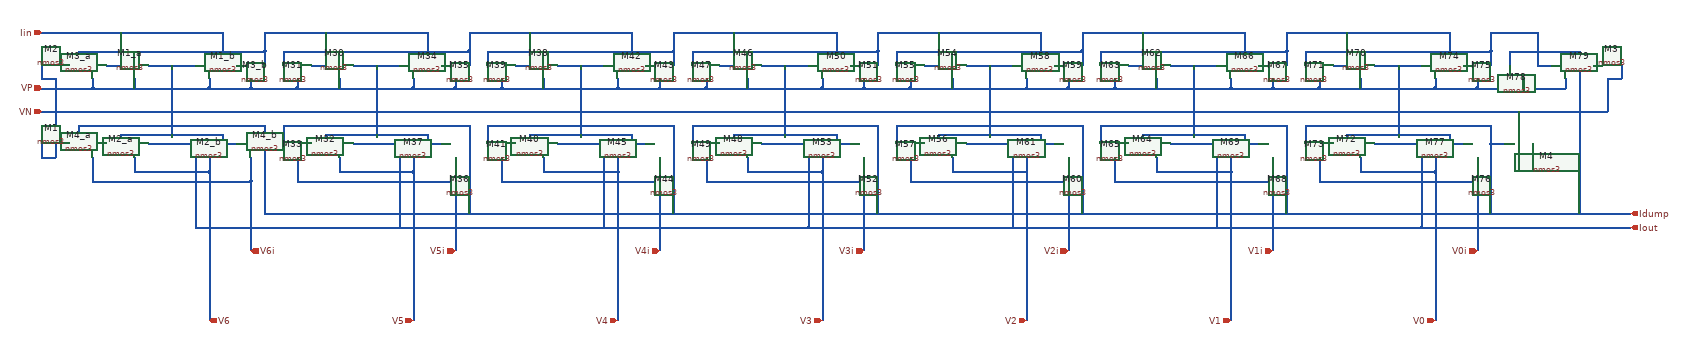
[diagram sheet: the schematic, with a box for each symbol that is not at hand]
v {xschem version=3.4.3 file_version=1.2
}
G {}
K {}
V {}
S {}
E {}
N 210 -770 210 -750 {
lab=VP}
N 210 -750 460 -750 {
lab=VP}
N 460 -770 460 -750 {
lab=VP}
N 300 -770 300 -750 {
lab=VP}
N 460 -750 550 -750 {
lab=VP}
N 550 -770 550 -750 {
lab=VP}
N 100 -750 210 -750 {
lab=VP}
N 330 -800 430 -800 {
lab=#net1}
N 330 -630 430 -630 {
lab=Iout}
N 210 -600 210 -570 {
lab=V6i}
N 300 -600 300 -570 {
lab=V6}
N 460 -600 460 -570 {
lab=V6}
N 240 -630 270 -630 {
lab=#net1}
N 240 -800 270 -800 {
lab=Iin}
N 490 -800 520 -800 {
lab=Iin}
N 180 -830 180 -800 {
lab=#net2}
N 180 -830 580 -830 {
lab=#net2}
N 580 -830 580 -800 {
lab=#net2}
N 580 -870 580 -830 {
lab=#net2}
N 300 -570 460 -570 {
lab=V6}
N 210 -570 210 -550 {
lab=V6i}
N 100 -870 490 -870 {
lab=Iin}
N 490 -870 490 -800 {
lab=Iin}
N 270 -870 270 -800 {
lab=Iin}
N 380 -800 380 -720 {
lab=#net1}
N 270 -650 270 -630 {
lab=#net1}
N 270 -650 490 -650 {
lab=#net1}
N 490 -650 490 -630 {
lab=#net1}
N 380 -720 380 -650 {
lab=#net1}
N 180 -670 180 -630 {
lab=Idump}
N 430 -630 430 -450 {
lab=Iout}
N 430 -450 490 -450 {
lab=Iout}
N 490 -450 620 -450 {
lab=Iout}
N 590 -480 620 -480 {
lab=Idump}
N 580 -870 620 -870 {
lab=#net2}
N 550 -600 550 -550 {
lab=V6i}
N 210 -550 550 -550 {
lab=V6i}
N 490 -630 520 -630 {
lab=#net1}
N 650 -770 650 -750 {
lab=VP}
N 650 -750 900 -750 {
lab=VP}
N 900 -770 900 -750 {
lab=VP}
N 740 -770 740 -750 {
lab=VP}
N 900 -750 990 -750 {
lab=VP}
N 990 -770 990 -750 {
lab=VP}
N 770 -800 870 -800 {
lab=#net3}
N 770 -630 870 -630 {
lab=Iout}
N 650 -600 650 -570 {
lab=V5i}
N 740 -600 740 -570 {
lab=V5}
N 900 -600 900 -570 {
lab=V5}
N 680 -630 710 -630 {
lab=#net3}
N 680 -800 710 -800 {
lab=#net2}
N 930 -800 960 -800 {
lab=#net2}
N 620 -830 620 -800 {
lab=#net4}
N 620 -830 1020 -830 {
lab=#net4}
N 1020 -830 1020 -800 {
lab=#net4}
N 1020 -870 1020 -830 {
lab=#net4}
N 740 -570 900 -570 {
lab=V5}
N 650 -570 650 -550 {
lab=V5i}
N 930 -870 930 -800 {
lab=#net2}
N 710 -870 710 -800 {
lab=#net2}
N 820 -800 820 -720 {
lab=#net3}
N 710 -650 710 -630 {
lab=#net3}
N 710 -650 930 -650 {
lab=#net3}
N 930 -650 930 -630 {
lab=#net3}
N 820 -720 820 -650 {
lab=#net3}
N 620 -670 620 -630 {
lab=Idump}
N 870 -630 870 -450 {
lab=Iout}
N 870 -450 930 -450 {
lab=Iout}
N 930 -450 1060 -450 {
lab=Iout}
N 1030 -480 1060 -480 {
lab=Idump}
N 1020 -870 1060 -870 {
lab=#net4}
N 990 -600 990 -550 {
lab=V5i}
N 650 -550 990 -550 {
lab=V5i}
N 930 -630 960 -630 {
lab=#net3}
N 620 -480 1030 -480 {
lab=Idump}
N 620 -450 870 -450 {
lab=Iout}
N 180 -670 580 -670 {
lab=Idump}
N 580 -670 580 -630 {
lab=Idump}
N 580 -630 580 -480 {
lab=Idump}
N 580 -480 590 -480 {
lab=Idump}
N 620 -670 1020 -670 {
lab=Idump}
N 1020 -670 1020 -630 {
lab=Idump}
N 1020 -630 1020 -480 {
lab=Idump}
N 620 -870 930 -870 {
lab=#net2}
N 1090 -770 1090 -750 {
lab=VP}
N 1090 -750 1340 -750 {
lab=VP}
N 1340 -770 1340 -750 {
lab=VP}
N 1180 -770 1180 -750 {
lab=VP}
N 1340 -750 1430 -750 {
lab=VP}
N 1430 -770 1430 -750 {
lab=VP}
N 1210 -800 1310 -800 {
lab=#net5}
N 1210 -630 1310 -630 {
lab=Iout}
N 1090 -600 1090 -570 {
lab=V4i}
N 1180 -600 1180 -570 {
lab=V4}
N 1340 -600 1340 -570 {
lab=V4}
N 1120 -630 1150 -630 {
lab=#net5}
N 1120 -800 1150 -800 {
lab=#net4}
N 1370 -800 1400 -800 {
lab=#net4}
N 1060 -830 1060 -800 {
lab=#net6}
N 1060 -830 1460 -830 {
lab=#net6}
N 1460 -830 1460 -800 {
lab=#net6}
N 1460 -870 1460 -830 {
lab=#net6}
N 1180 -570 1340 -570 {
lab=V4}
N 1090 -570 1090 -550 {
lab=V4i}
N 1370 -870 1370 -800 {
lab=#net4}
N 1150 -870 1150 -800 {
lab=#net4}
N 1260 -800 1260 -720 {
lab=#net5}
N 1150 -650 1150 -630 {
lab=#net5}
N 1150 -650 1370 -650 {
lab=#net5}
N 1370 -650 1370 -630 {
lab=#net5}
N 1260 -720 1260 -650 {
lab=#net5}
N 1060 -670 1060 -630 {
lab=Idump}
N 1310 -630 1310 -450 {
lab=Iout}
N 1310 -450 1370 -450 {
lab=Iout}
N 1370 -450 1500 -450 {
lab=Iout}
N 1470 -480 1500 -480 {
lab=Idump}
N 1460 -870 1500 -870 {
lab=#net6}
N 1430 -600 1430 -550 {
lab=V4i}
N 1090 -550 1430 -550 {
lab=V4i}
N 1370 -630 1400 -630 {
lab=#net5}
N 1060 -480 1470 -480 {
lab=Idump}
N 1060 -450 1310 -450 {
lab=Iout}
N 1060 -670 1460 -670 {
lab=Idump}
N 1460 -670 1460 -630 {
lab=Idump}
N 1460 -630 1460 -480 {
lab=Idump}
N 1060 -870 1370 -870 {
lab=#net4}
N 1530 -770 1530 -750 {
lab=VP}
N 1530 -750 1780 -750 {
lab=VP}
N 1780 -770 1780 -750 {
lab=VP}
N 1620 -770 1620 -750 {
lab=VP}
N 1780 -750 1870 -750 {
lab=VP}
N 1870 -770 1870 -750 {
lab=VP}
N 1650 -800 1750 -800 {
lab=#net7}
N 1650 -630 1750 -630 {
lab=Iout}
N 1530 -600 1530 -570 {
lab=V3i}
N 1620 -600 1620 -570 {
lab=V3}
N 1780 -600 1780 -570 {
lab=V3}
N 1560 -630 1590 -630 {
lab=#net7}
N 1560 -800 1590 -800 {
lab=#net6}
N 1810 -800 1840 -800 {
lab=#net6}
N 1500 -830 1500 -800 {
lab=#net8}
N 1500 -830 1900 -830 {
lab=#net8}
N 1900 -830 1900 -800 {
lab=#net8}
N 1900 -870 1900 -830 {
lab=#net8}
N 1620 -570 1780 -570 {
lab=V3}
N 1530 -570 1530 -550 {
lab=V3i}
N 1810 -870 1810 -800 {
lab=#net6}
N 1590 -870 1590 -800 {
lab=#net6}
N 1700 -800 1700 -720 {
lab=#net7}
N 1590 -650 1590 -630 {
lab=#net7}
N 1590 -650 1810 -650 {
lab=#net7}
N 1810 -650 1810 -630 {
lab=#net7}
N 1700 -720 1700 -650 {
lab=#net7}
N 1500 -670 1500 -630 {
lab=Idump}
N 1750 -630 1750 -450 {
lab=Iout}
N 1750 -450 1810 -450 {
lab=Iout}
N 1810 -450 1940 -450 {
lab=Iout}
N 1910 -480 1940 -480 {
lab=Idump}
N 1900 -870 1940 -870 {
lab=#net8}
N 1870 -600 1870 -550 {
lab=V3i}
N 1530 -550 1870 -550 {
lab=V3i}
N 1810 -630 1840 -630 {
lab=#net7}
N 1500 -480 1910 -480 {
lab=Idump}
N 1500 -450 1750 -450 {
lab=Iout}
N 1500 -670 1900 -670 {
lab=Idump}
N 1900 -670 1900 -630 {
lab=Idump}
N 1900 -630 1900 -480 {
lab=Idump}
N 1500 -870 1810 -870 {
lab=#net6}
N 1970 -770 1970 -750 {
lab=VP}
N 1970 -750 2220 -750 {
lab=VP}
N 2220 -770 2220 -750 {
lab=VP}
N 2060 -770 2060 -750 {
lab=VP}
N 2220 -750 2310 -750 {
lab=VP}
N 2310 -770 2310 -750 {
lab=VP}
N 2090 -800 2190 -800 {
lab=#net9}
N 2090 -630 2190 -630 {
lab=Iout}
N 1970 -600 1970 -570 {
lab=V2i}
N 2060 -600 2060 -570 {
lab=V2}
N 2220 -600 2220 -570 {
lab=V2}
N 2000 -630 2030 -630 {
lab=#net9}
N 2000 -800 2030 -800 {
lab=#net8}
N 2250 -800 2280 -800 {
lab=#net8}
N 1940 -830 1940 -800 {
lab=#net10}
N 1940 -830 2340 -830 {
lab=#net10}
N 2340 -830 2340 -800 {
lab=#net10}
N 2340 -870 2340 -830 {
lab=#net10}
N 2060 -570 2220 -570 {
lab=V2}
N 1970 -570 1970 -550 {
lab=V2i}
N 2250 -870 2250 -800 {
lab=#net8}
N 2030 -870 2030 -800 {
lab=#net8}
N 2140 -800 2140 -720 {
lab=#net9}
N 2030 -650 2030 -630 {
lab=#net9}
N 2030 -650 2250 -650 {
lab=#net9}
N 2250 -650 2250 -630 {
lab=#net9}
N 2140 -720 2140 -650 {
lab=#net9}
N 1940 -670 1940 -630 {
lab=Idump}
N 2190 -630 2190 -450 {
lab=Iout}
N 2190 -450 2250 -450 {
lab=Iout}
N 2250 -450 2380 -450 {
lab=Iout}
N 2350 -480 2380 -480 {
lab=Idump}
N 2340 -870 2380 -870 {
lab=#net10}
N 2310 -600 2310 -550 {
lab=V2i}
N 1970 -550 2310 -550 {
lab=V2i}
N 2250 -630 2280 -630 {
lab=#net9}
N 1940 -480 2350 -480 {
lab=Idump}
N 1940 -450 2190 -450 {
lab=Iout}
N 1940 -670 2340 -670 {
lab=Idump}
N 2340 -670 2340 -630 {
lab=Idump}
N 2340 -630 2340 -480 {
lab=Idump}
N 1940 -870 2250 -870 {
lab=#net8}
N 2410 -770 2410 -750 {
lab=VP}
N 2410 -750 2660 -750 {
lab=VP}
N 2660 -770 2660 -750 {
lab=VP}
N 2500 -770 2500 -750 {
lab=VP}
N 2660 -750 2750 -750 {
lab=VP}
N 2750 -770 2750 -750 {
lab=VP}
N 2530 -800 2630 -800 {
lab=#net11}
N 2530 -630 2630 -630 {
lab=Iout}
N 2410 -600 2410 -570 {
lab=V1i}
N 2500 -600 2500 -570 {
lab=V1}
N 2660 -600 2660 -570 {
lab=V1}
N 2440 -630 2470 -630 {
lab=#net11}
N 2440 -800 2470 -800 {
lab=#net10}
N 2690 -800 2720 -800 {
lab=#net10}
N 2380 -830 2380 -800 {
lab=#net12}
N 2380 -830 2780 -830 {
lab=#net12}
N 2780 -830 2780 -800 {
lab=#net12}
N 2780 -870 2780 -830 {
lab=#net12}
N 2500 -570 2660 -570 {
lab=V1}
N 2410 -570 2410 -550 {
lab=V1i}
N 2690 -870 2690 -800 {
lab=#net10}
N 2470 -870 2470 -800 {
lab=#net10}
N 2580 -800 2580 -720 {
lab=#net11}
N 2470 -650 2470 -630 {
lab=#net11}
N 2470 -650 2690 -650 {
lab=#net11}
N 2690 -650 2690 -630 {
lab=#net11}
N 2580 -720 2580 -650 {
lab=#net11}
N 2380 -670 2380 -630 {
lab=Idump}
N 2630 -630 2630 -450 {
lab=Iout}
N 2630 -450 2690 -450 {
lab=Iout}
N 2690 -450 2820 -450 {
lab=Iout}
N 2790 -480 2820 -480 {
lab=Idump}
N 2780 -870 2820 -870 {
lab=#net12}
N 2750 -600 2750 -550 {
lab=V1i}
N 2410 -550 2750 -550 {
lab=V1i}
N 2690 -630 2720 -630 {
lab=#net11}
N 2380 -480 2790 -480 {
lab=Idump}
N 2380 -450 2630 -450 {
lab=Iout}
N 2380 -670 2780 -670 {
lab=Idump}
N 2780 -670 2780 -630 {
lab=Idump}
N 2780 -630 2780 -480 {
lab=Idump}
N 2380 -870 2690 -870 {
lab=#net10}
N 2850 -770 2850 -750 {
lab=VP}
N 2850 -750 3100 -750 {
lab=VP}
N 3100 -770 3100 -750 {
lab=VP}
N 2940 -770 2940 -750 {
lab=VP}
N 3100 -750 3190 -750 {
lab=VP}
N 3190 -770 3190 -750 {
lab=VP}
N 2970 -800 3070 -800 {
lab=#net13}
N 2970 -630 3070 -630 {
lab=Iout}
N 2850 -600 2850 -570 {
lab=V0}
N 2940 -600 2940 -570 {
lab=V0}
N 3100 -600 3100 -570 {
lab=V0}
N 2880 -630 2910 -630 {
lab=#net13}
N 2880 -800 2910 -800 {
lab=#net12}
N 3130 -800 3160 -800 {
lab=#net12}
N 2820 -830 2820 -800 {
lab=#net14}
N 2820 -830 3220 -830 {
lab=#net14}
N 3220 -830 3220 -800 {
lab=#net14}
N 3220 -870 3220 -830 {
lab=#net14}
N 2940 -570 3100 -570 {
lab=V0}
N 2850 -570 2850 -550 {
lab=V0}
N 3130 -870 3130 -800 {
lab=#net12}
N 2910 -870 2910 -800 {
lab=#net12}
N 3020 -800 3020 -720 {
lab=#net13}
N 2910 -650 2910 -630 {
lab=#net13}
N 2910 -650 3130 -650 {
lab=#net13}
N 3130 -650 3130 -630 {
lab=#net13}
N 3020 -720 3020 -650 {
lab=#net13}
N 2820 -670 2820 -630 {
lab=Idump}
N 3070 -630 3070 -450 {
lab=Iout}
N 3070 -450 3130 -450 {
lab=Iout}
N 3130 -450 3260 -450 {
lab=Iout}
N 3230 -480 3260 -480 {
lab=Idump}
N 3220 -870 3260 -870 {
lab=#net14}
N 3190 -600 3190 -550 {
lab=V0}
N 2850 -550 3190 -550 {
lab=V0}
N 3130 -630 3160 -630 {
lab=#net13}
N 2820 -480 3230 -480 {
lab=Idump}
N 2820 -450 3070 -450 {
lab=Iout}
N 2820 -670 3220 -670 {
lab=Idump}
N 3220 -670 3220 -630 {
lab=Idump}
N 3220 -630 3220 -480 {
lab=Idump}
N 2820 -870 3130 -870 {
lab=#net12}
N 3320 -800 3350 -800 {
lab=#net14}
N 3260 -870 3320 -870 {
lab=#net14}
N 3320 -870 3320 -800 {
lab=#net14}
N 550 -750 650 -750 {
lab=VP}
N 990 -750 1090 -750 {
lab=VP}
N 1430 -750 1530 -750 {
lab=VP}
N 1870 -750 1970 -750 {
lab=VP}
N 2310 -750 2410 -750 {
lab=VP}
N 2750 -750 2850 -750 {
lab=VP}
N 3190 -750 3380 -750 {
lab=VP}
N 3380 -770 3380 -750 {
lab=VP}
N 3290 -770 3290 -750 {
lab=VP}
N 3260 -830 3260 -800 {
lab=Idump}
N 3260 -830 3410 -830 {
lab=Idump}
N 3410 -830 3410 -800 {
lab=Idump}
N 3260 -480 3440 -480 {
lab=Idump}
N 3260 -450 3440 -450 {
lab=Iout}
N 3410 -800 3410 -480 {
lab=Idump}
N 460 -400 460 -250 {
lab=V6}
N 900 -400 900 -250 {
lab=V5}
N 1340 -400 1340 -250 {
lab=V4}
N 1780 -400 1780 -250 {
lab=V3}
N 2220 -400 2220 -250 {
lab=V2}
N 2660 -400 2660 -250 {
lab=V1}
N 3100 -400 3100 -250 {
lab=V0}
N 160 -630 180 -630 {
lab=Idump}
N 100 -630 100 -600 {
lab=VN}
N 100 -600 130 -600 {
lab=VN}
N 100 -800 100 -770 {
lab=VN}
N 100 -770 130 -770 {
lab=VN}
N 160 -800 180 -800 {
lab=#net2}
N 3410 -800 3440 -800 {
lab=Idump}
N 3500 -800 3500 -770 {
lab=VN}
N 3470 -770 3500 -770 {
lab=VN}
N 100 -700 970 -700 {
lab=VN}
N 970 -700 1860 -700 {
lab=VN}
N 1860 -700 2980 -700 {
lab=VN}
N 2980 -700 3470 -700 {
lab=VN}
N 3470 -770 3470 -700 {
lab=VN}
N 3220 -630 3250 -630 {
lab=Idump}
N 3280 -600 3310 -600 {
lab=VN}
N 3310 -630 3310 -600 {
lab=VN}
N 3280 -700 3280 -600 {
lab=VN}
N 130 -770 130 -700 {
lab=VN}
N 130 -700 130 -600 {
lab=VN}
N 460 -570 460 -400 {
lab=V6}
N 550 -550 550 -400 {
lab=V6i}
N 900 -570 900 -400 {
lab=V5}
N 990 -550 990 -400 {
lab=V5i}
N 1340 -570 1340 -400 {
lab=V4}
N 1430 -550 1430 -400 {
lab=V4i}
N 1780 -570 1780 -400 {
lab=V3}
N 1870 -550 1870 -400 {
lab=V3i}
N 2220 -570 2220 -400 {
lab=V2}
N 2310 -550 2310 -400 {
lab=V2i}
N 2660 -570 2660 -400 {
lab=V1}
N 2750 -550 2750 -400 {
lab=V1i}
N 3100 -570 3100 -400 {
lab=V0}
N 3190 -550 3190 -400 {
lab=V0}
N 3440 -480 3520 -480 {
lab=Idump}
N 3440 -450 3520 -450 {
lab=Iout}
C {madvlsi/nmos3.sym} 300 -800 3 0 {name=M1_a
L=8

body=GND
nf=1
mult=1
ad="'int((nf+1)/2) * W/nf * 0.29'" 
pd="'2*int((nf+1)/2) * (W/nf + 0.29)'"
as="'int((nf+2)/2) * W/nf * 0.29'" 
ps="'2*int((nf+2)/2) * (W/nf + 0.29)'"
nrd="'0.29 / W'" nrs="'0.29 / W'"
sa=0 sb=0 sd=0
model=nfet_01v8
spiceprefix=X
W=0.5}
C {madvlsi/nmos3.sym} 210 -800 1 1 {name=M3_a
L=8

body=GND
nf=1
mult=1
ad="'int((nf+1)/2) * W/nf * 0.29'" 
pd="'2*int((nf+1)/2) * (W/nf + 0.29)'"
as="'int((nf+2)/2) * W/nf * 0.29'" 
ps="'2*int((nf+2)/2) * (W/nf + 0.29)'"
nrd="'0.29 / W'" nrs="'0.29 / W'"
sa=0 sb=0 sd=0
model=nfet_01v8
spiceprefix=X
W=0.5}
C {madvlsi/nmos3.sym} 300 -630 3 0 {name=M2_a
L=8

body=GND
nf=1
mult=1
ad="'int((nf+1)/2) * W/nf * 0.29'" 
pd="'2*int((nf+1)/2) * (W/nf + 0.29)'"
as="'int((nf+2)/2) * W/nf * 0.29'" 
ps="'2*int((nf+2)/2) * (W/nf + 0.29)'"
nrd="'0.29 / W'" nrs="'0.29 / W'"
sa=0 sb=0 sd=0
model=nfet_01v8
spiceprefix=X
W=0.5}
C {madvlsi/nmos3.sym} 210 -630 1 1 {name=M4_a
L=8

body=GND
nf=1
mult=1
ad="'int((nf+1)/2) * W/nf * 0.29'" 
pd="'2*int((nf+1)/2) * (W/nf + 0.29)'"
as="'int((nf+2)/2) * W/nf * 0.29'" 
ps="'2*int((nf+2)/2) * (W/nf + 0.29)'"
nrd="'0.29 / W'" nrs="'0.29 / W'"
sa=0 sb=0 sd=0
model=nfet_01v8
spiceprefix=X
W=0.5}
C {madvlsi/nmos3.sym} 460 -800 1 1 {name=M1_b
L=8

body=GND
nf=1
mult=1
ad="'int((nf+1)/2) * W/nf * 0.29'" 
pd="'2*int((nf+1)/2) * (W/nf + 0.29)'"
as="'int((nf+2)/2) * W/nf * 0.29'" 
ps="'2*int((nf+2)/2) * (W/nf + 0.29)'"
nrd="'0.29 / W'" nrs="'0.29 / W'"
sa=0 sb=0 sd=0
model=nfet_01v8
spiceprefix=X
W=0.5}
C {madvlsi/nmos3.sym} 550 -800 3 0 {name=M3_b
L=8

body=GND
nf=1
mult=1
ad="'int((nf+1)/2) * W/nf * 0.29'" 
pd="'2*int((nf+1)/2) * (W/nf + 0.29)'"
as="'int((nf+2)/2) * W/nf * 0.29'" 
ps="'2*int((nf+2)/2) * (W/nf + 0.29)'"
nrd="'0.29 / W'" nrs="'0.29 / W'"
sa=0 sb=0 sd=0
model=nfet_01v8
spiceprefix=X
W=0.5}
C {madvlsi/nmos3.sym} 550 -630 3 0 {name=M4_b
L=8

body=GND
nf=1
mult=1
ad="'int((nf+1)/2) * W/nf * 0.29'" 
pd="'2*int((nf+1)/2) * (W/nf + 0.29)'"
as="'int((nf+2)/2) * W/nf * 0.29'" 
ps="'2*int((nf+2)/2) * (W/nf + 0.29)'"
nrd="'0.29 / W'" nrs="'0.29 / W'"
sa=0 sb=0 sd=0
model=nfet_01v8
spiceprefix=X
W=0.5}
C {madvlsi/nmos3.sym} 460 -630 1 1 {name=M2_b
L=8

body=GND
nf=1
mult=1
ad="'int((nf+1)/2) * W/nf * 0.29'" 
pd="'2*int((nf+1)/2) * (W/nf + 0.29)'"
as="'int((nf+2)/2) * W/nf * 0.29'" 
ps="'2*int((nf+2)/2) * (W/nf + 0.29)'"
nrd="'0.29 / W'" nrs="'0.29 / W'"
sa=0 sb=0 sd=0
model=nfet_01v8
spiceprefix=X
W=0.5}
C {devices/iopin.sym} 100 -750 2 0 {name=p14 lab=VP}
C {devices/iopin.sym} 100 -870 2 0 {name=p15 lab=Iin}
C {madvlsi/nmos3.sym} 740 -800 3 0 {name=M30
L=8

body=GND
nf=1
mult=1
ad="'int((nf+1)/2) * W/nf * 0.29'" 
pd="'2*int((nf+1)/2) * (W/nf + 0.29)'"
as="'int((nf+2)/2) * W/nf * 0.29'" 
ps="'2*int((nf+2)/2) * (W/nf + 0.29)'"
nrd="'0.29 / W'" nrs="'0.29 / W'"
sa=0 sb=0 sd=0
model=nfet_01v8
spiceprefix=X
W=0.5}
C {madvlsi/nmos3.sym} 650 -800 1 1 {name=M31
L=8

body=GND
nf=1
mult=1
ad="'int((nf+1)/2) * W/nf * 0.29'" 
pd="'2*int((nf+1)/2) * (W/nf + 0.29)'"
as="'int((nf+2)/2) * W/nf * 0.29'" 
ps="'2*int((nf+2)/2) * (W/nf + 0.29)'"
nrd="'0.29 / W'" nrs="'0.29 / W'"
sa=0 sb=0 sd=0
model=nfet_01v8
spiceprefix=X
W=0.5}
C {madvlsi/nmos3.sym} 740 -630 3 0 {name=M32
L=8

body=GND
nf=1
mult=1
ad="'int((nf+1)/2) * W/nf * 0.29'" 
pd="'2*int((nf+1)/2) * (W/nf + 0.29)'"
as="'int((nf+2)/2) * W/nf * 0.29'" 
ps="'2*int((nf+2)/2) * (W/nf + 0.29)'"
nrd="'0.29 / W'" nrs="'0.29 / W'"
sa=0 sb=0 sd=0
model=nfet_01v8
spiceprefix=X
W=0.5}
C {madvlsi/nmos3.sym} 650 -630 1 1 {name=M33
L=8

body=GND
nf=1
mult=1
ad="'int((nf+1)/2) * W/nf * 0.29'" 
pd="'2*int((nf+1)/2) * (W/nf + 0.29)'"
as="'int((nf+2)/2) * W/nf * 0.29'" 
ps="'2*int((nf+2)/2) * (W/nf + 0.29)'"
nrd="'0.29 / W'" nrs="'0.29 / W'"
sa=0 sb=0 sd=0
model=nfet_01v8
spiceprefix=X
W=0.5}
C {madvlsi/nmos3.sym} 900 -800 1 1 {name=M34
L=8

body=GND
nf=1
mult=1
ad="'int((nf+1)/2) * W/nf * 0.29'" 
pd="'2*int((nf+1)/2) * (W/nf + 0.29)'"
as="'int((nf+2)/2) * W/nf * 0.29'" 
ps="'2*int((nf+2)/2) * (W/nf + 0.29)'"
nrd="'0.29 / W'" nrs="'0.29 / W'"
sa=0 sb=0 sd=0
model=nfet_01v8
spiceprefix=X
W=0.5}
C {madvlsi/nmos3.sym} 990 -800 3 0 {name=M35
L=8

body=GND
nf=1
mult=1
ad="'int((nf+1)/2) * W/nf * 0.29'" 
pd="'2*int((nf+1)/2) * (W/nf + 0.29)'"
as="'int((nf+2)/2) * W/nf * 0.29'" 
ps="'2*int((nf+2)/2) * (W/nf + 0.29)'"
nrd="'0.29 / W'" nrs="'0.29 / W'"
sa=0 sb=0 sd=0
model=nfet_01v8
spiceprefix=X
W=0.5}
C {madvlsi/nmos3.sym} 990 -630 3 0 {name=M36
L=8

body=GND
nf=1
mult=1
ad="'int((nf+1)/2) * W/nf * 0.29'" 
pd="'2*int((nf+1)/2) * (W/nf + 0.29)'"
as="'int((nf+2)/2) * W/nf * 0.29'" 
ps="'2*int((nf+2)/2) * (W/nf + 0.29)'"
nrd="'0.29 / W'" nrs="'0.29 / W'"
sa=0 sb=0 sd=0
model=nfet_01v8
spiceprefix=X
W=0.5}
C {madvlsi/nmos3.sym} 900 -630 1 1 {name=M37
L=8

body=GND
nf=1
mult=1
ad="'int((nf+1)/2) * W/nf * 0.29'" 
pd="'2*int((nf+1)/2) * (W/nf + 0.29)'"
as="'int((nf+2)/2) * W/nf * 0.29'" 
ps="'2*int((nf+2)/2) * (W/nf + 0.29)'"
nrd="'0.29 / W'" nrs="'0.29 / W'"
sa=0 sb=0 sd=0
model=nfet_01v8
spiceprefix=X
W=0.5}
C {madvlsi/nmos3.sym} 1180 -800 3 0 {name=M38
L=8

body=GND
nf=1
mult=1
ad="'int((nf+1)/2) * W/nf * 0.29'" 
pd="'2*int((nf+1)/2) * (W/nf + 0.29)'"
as="'int((nf+2)/2) * W/nf * 0.29'" 
ps="'2*int((nf+2)/2) * (W/nf + 0.29)'"
nrd="'0.29 / W'" nrs="'0.29 / W'"
sa=0 sb=0 sd=0
model=nfet_01v8
spiceprefix=X
W=0.5}
C {madvlsi/nmos3.sym} 1090 -800 1 1 {name=M39
L=8

body=GND
nf=1
mult=1
ad="'int((nf+1)/2) * W/nf * 0.29'" 
pd="'2*int((nf+1)/2) * (W/nf + 0.29)'"
as="'int((nf+2)/2) * W/nf * 0.29'" 
ps="'2*int((nf+2)/2) * (W/nf + 0.29)'"
nrd="'0.29 / W'" nrs="'0.29 / W'"
sa=0 sb=0 sd=0
model=nfet_01v8
spiceprefix=X
W=0.5}
C {madvlsi/nmos3.sym} 1180 -630 3 0 {name=M40
L=8

body=GND
nf=1
mult=1
ad="'int((nf+1)/2) * W/nf * 0.29'" 
pd="'2*int((nf+1)/2) * (W/nf + 0.29)'"
as="'int((nf+2)/2) * W/nf * 0.29'" 
ps="'2*int((nf+2)/2) * (W/nf + 0.29)'"
nrd="'0.29 / W'" nrs="'0.29 / W'"
sa=0 sb=0 sd=0
model=nfet_01v8
spiceprefix=X
W=0.5}
C {madvlsi/nmos3.sym} 1090 -630 1 1 {name=M41
L=8

body=GND
nf=1
mult=1
ad="'int((nf+1)/2) * W/nf * 0.29'" 
pd="'2*int((nf+1)/2) * (W/nf + 0.29)'"
as="'int((nf+2)/2) * W/nf * 0.29'" 
ps="'2*int((nf+2)/2) * (W/nf + 0.29)'"
nrd="'0.29 / W'" nrs="'0.29 / W'"
sa=0 sb=0 sd=0
model=nfet_01v8
spiceprefix=X
W=0.5}
C {madvlsi/nmos3.sym} 1340 -800 1 1 {name=M42
L=8

body=GND
nf=1
mult=1
ad="'int((nf+1)/2) * W/nf * 0.29'" 
pd="'2*int((nf+1)/2) * (W/nf + 0.29)'"
as="'int((nf+2)/2) * W/nf * 0.29'" 
ps="'2*int((nf+2)/2) * (W/nf + 0.29)'"
nrd="'0.29 / W'" nrs="'0.29 / W'"
sa=0 sb=0 sd=0
model=nfet_01v8
spiceprefix=X
W=0.5}
C {madvlsi/nmos3.sym} 1430 -800 3 0 {name=M43
L=8

body=GND
nf=1
mult=1
ad="'int((nf+1)/2) * W/nf * 0.29'" 
pd="'2*int((nf+1)/2) * (W/nf + 0.29)'"
as="'int((nf+2)/2) * W/nf * 0.29'" 
ps="'2*int((nf+2)/2) * (W/nf + 0.29)'"
nrd="'0.29 / W'" nrs="'0.29 / W'"
sa=0 sb=0 sd=0
model=nfet_01v8
spiceprefix=X
W=0.5}
C {madvlsi/nmos3.sym} 1430 -630 3 0 {name=M44
L=8

body=GND
nf=1
mult=1
ad="'int((nf+1)/2) * W/nf * 0.29'" 
pd="'2*int((nf+1)/2) * (W/nf + 0.29)'"
as="'int((nf+2)/2) * W/nf * 0.29'" 
ps="'2*int((nf+2)/2) * (W/nf + 0.29)'"
nrd="'0.29 / W'" nrs="'0.29 / W'"
sa=0 sb=0 sd=0
model=nfet_01v8
spiceprefix=X
W=0.5}
C {madvlsi/nmos3.sym} 1340 -630 1 1 {name=M45
L=8

body=GND
nf=1
mult=1
ad="'int((nf+1)/2) * W/nf * 0.29'" 
pd="'2*int((nf+1)/2) * (W/nf + 0.29)'"
as="'int((nf+2)/2) * W/nf * 0.29'" 
ps="'2*int((nf+2)/2) * (W/nf + 0.29)'"
nrd="'0.29 / W'" nrs="'0.29 / W'"
sa=0 sb=0 sd=0
model=nfet_01v8
spiceprefix=X
W=0.5}
C {madvlsi/nmos3.sym} 1620 -800 3 0 {name=M46
L=8

body=GND
nf=1
mult=1
ad="'int((nf+1)/2) * W/nf * 0.29'" 
pd="'2*int((nf+1)/2) * (W/nf + 0.29)'"
as="'int((nf+2)/2) * W/nf * 0.29'" 
ps="'2*int((nf+2)/2) * (W/nf + 0.29)'"
nrd="'0.29 / W'" nrs="'0.29 / W'"
sa=0 sb=0 sd=0
model=nfet_01v8
spiceprefix=X
W=0.5}
C {madvlsi/nmos3.sym} 1530 -800 1 1 {name=M47
L=8

body=GND
nf=1
mult=1
ad="'int((nf+1)/2) * W/nf * 0.29'" 
pd="'2*int((nf+1)/2) * (W/nf + 0.29)'"
as="'int((nf+2)/2) * W/nf * 0.29'" 
ps="'2*int((nf+2)/2) * (W/nf + 0.29)'"
nrd="'0.29 / W'" nrs="'0.29 / W'"
sa=0 sb=0 sd=0
model=nfet_01v8
spiceprefix=X
W=0.5}
C {madvlsi/nmos3.sym} 1620 -630 3 0 {name=M48
L=8

body=GND
nf=1
mult=1
ad="'int((nf+1)/2) * W/nf * 0.29'" 
pd="'2*int((nf+1)/2) * (W/nf + 0.29)'"
as="'int((nf+2)/2) * W/nf * 0.29'" 
ps="'2*int((nf+2)/2) * (W/nf + 0.29)'"
nrd="'0.29 / W'" nrs="'0.29 / W'"
sa=0 sb=0 sd=0
model=nfet_01v8
spiceprefix=X
W=0.5}
C {madvlsi/nmos3.sym} 1530 -630 1 1 {name=M49
L=8

body=GND
nf=1
mult=1
ad="'int((nf+1)/2) * W/nf * 0.29'" 
pd="'2*int((nf+1)/2) * (W/nf + 0.29)'"
as="'int((nf+2)/2) * W/nf * 0.29'" 
ps="'2*int((nf+2)/2) * (W/nf + 0.29)'"
nrd="'0.29 / W'" nrs="'0.29 / W'"
sa=0 sb=0 sd=0
model=nfet_01v8
spiceprefix=X
W=0.5}
C {madvlsi/nmos3.sym} 1780 -800 1 1 {name=M50
L=8

body=GND
nf=1
mult=1
ad="'int((nf+1)/2) * W/nf * 0.29'" 
pd="'2*int((nf+1)/2) * (W/nf + 0.29)'"
as="'int((nf+2)/2) * W/nf * 0.29'" 
ps="'2*int((nf+2)/2) * (W/nf + 0.29)'"
nrd="'0.29 / W'" nrs="'0.29 / W'"
sa=0 sb=0 sd=0
model=nfet_01v8
spiceprefix=X
W=0.5}
C {madvlsi/nmos3.sym} 1870 -800 3 0 {name=M51
L=8

body=GND
nf=1
mult=1
ad="'int((nf+1)/2) * W/nf * 0.29'" 
pd="'2*int((nf+1)/2) * (W/nf + 0.29)'"
as="'int((nf+2)/2) * W/nf * 0.29'" 
ps="'2*int((nf+2)/2) * (W/nf + 0.29)'"
nrd="'0.29 / W'" nrs="'0.29 / W'"
sa=0 sb=0 sd=0
model=nfet_01v8
spiceprefix=X
W=0.5}
C {madvlsi/nmos3.sym} 1870 -630 3 0 {name=M52
L=8

body=GND
nf=1
mult=1
ad="'int((nf+1)/2) * W/nf * 0.29'" 
pd="'2*int((nf+1)/2) * (W/nf + 0.29)'"
as="'int((nf+2)/2) * W/nf * 0.29'" 
ps="'2*int((nf+2)/2) * (W/nf + 0.29)'"
nrd="'0.29 / W'" nrs="'0.29 / W'"
sa=0 sb=0 sd=0
model=nfet_01v8
spiceprefix=X
W=0.5}
C {madvlsi/nmos3.sym} 1780 -630 1 1 {name=M53
L=8

body=GND
nf=1
mult=1
ad="'int((nf+1)/2) * W/nf * 0.29'" 
pd="'2*int((nf+1)/2) * (W/nf + 0.29)'"
as="'int((nf+2)/2) * W/nf * 0.29'" 
ps="'2*int((nf+2)/2) * (W/nf + 0.29)'"
nrd="'0.29 / W'" nrs="'0.29 / W'"
sa=0 sb=0 sd=0
model=nfet_01v8
spiceprefix=X
W=0.5}
C {madvlsi/nmos3.sym} 2060 -800 3 0 {name=M54
L=8

body=GND
nf=1
mult=1
ad="'int((nf+1)/2) * W/nf * 0.29'" 
pd="'2*int((nf+1)/2) * (W/nf + 0.29)'"
as="'int((nf+2)/2) * W/nf * 0.29'" 
ps="'2*int((nf+2)/2) * (W/nf + 0.29)'"
nrd="'0.29 / W'" nrs="'0.29 / W'"
sa=0 sb=0 sd=0
model=nfet_01v8
spiceprefix=X
W=0.5}
C {madvlsi/nmos3.sym} 1970 -800 1 1 {name=M55
L=8

body=GND
nf=1
mult=1
ad="'int((nf+1)/2) * W/nf * 0.29'" 
pd="'2*int((nf+1)/2) * (W/nf + 0.29)'"
as="'int((nf+2)/2) * W/nf * 0.29'" 
ps="'2*int((nf+2)/2) * (W/nf + 0.29)'"
nrd="'0.29 / W'" nrs="'0.29 / W'"
sa=0 sb=0 sd=0
model=nfet_01v8
spiceprefix=X
W=0.5}
C {madvlsi/nmos3.sym} 2060 -630 3 0 {name=M56
L=8

body=GND
nf=1
mult=1
ad="'int((nf+1)/2) * W/nf * 0.29'" 
pd="'2*int((nf+1)/2) * (W/nf + 0.29)'"
as="'int((nf+2)/2) * W/nf * 0.29'" 
ps="'2*int((nf+2)/2) * (W/nf + 0.29)'"
nrd="'0.29 / W'" nrs="'0.29 / W'"
sa=0 sb=0 sd=0
model=nfet_01v8
spiceprefix=X
W=0.5}
C {madvlsi/nmos3.sym} 1970 -630 1 1 {name=M57
L=8

body=GND
nf=1
mult=1
ad="'int((nf+1)/2) * W/nf * 0.29'" 
pd="'2*int((nf+1)/2) * (W/nf + 0.29)'"
as="'int((nf+2)/2) * W/nf * 0.29'" 
ps="'2*int((nf+2)/2) * (W/nf + 0.29)'"
nrd="'0.29 / W'" nrs="'0.29 / W'"
sa=0 sb=0 sd=0
model=nfet_01v8
spiceprefix=X
W=0.5}
C {madvlsi/nmos3.sym} 2220 -800 1 1 {name=M58
L=8

body=GND
nf=1
mult=1
ad="'int((nf+1)/2) * W/nf * 0.29'" 
pd="'2*int((nf+1)/2) * (W/nf + 0.29)'"
as="'int((nf+2)/2) * W/nf * 0.29'" 
ps="'2*int((nf+2)/2) * (W/nf + 0.29)'"
nrd="'0.29 / W'" nrs="'0.29 / W'"
sa=0 sb=0 sd=0
model=nfet_01v8
spiceprefix=X
W=0.5}
C {madvlsi/nmos3.sym} 2310 -800 3 0 {name=M59
L=8

body=GND
nf=1
mult=1
ad="'int((nf+1)/2) * W/nf * 0.29'" 
pd="'2*int((nf+1)/2) * (W/nf + 0.29)'"
as="'int((nf+2)/2) * W/nf * 0.29'" 
ps="'2*int((nf+2)/2) * (W/nf + 0.29)'"
nrd="'0.29 / W'" nrs="'0.29 / W'"
sa=0 sb=0 sd=0
model=nfet_01v8
spiceprefix=X
W=0.5}
C {madvlsi/nmos3.sym} 2310 -630 3 0 {name=M60
L=8

body=GND
nf=1
mult=1
ad="'int((nf+1)/2) * W/nf * 0.29'" 
pd="'2*int((nf+1)/2) * (W/nf + 0.29)'"
as="'int((nf+2)/2) * W/nf * 0.29'" 
ps="'2*int((nf+2)/2) * (W/nf + 0.29)'"
nrd="'0.29 / W'" nrs="'0.29 / W'"
sa=0 sb=0 sd=0
model=nfet_01v8
spiceprefix=X
W=0.5}
C {madvlsi/nmos3.sym} 2220 -630 1 1 {name=M61
L=8

body=GND
nf=1
mult=1
ad="'int((nf+1)/2) * W/nf * 0.29'" 
pd="'2*int((nf+1)/2) * (W/nf + 0.29)'"
as="'int((nf+2)/2) * W/nf * 0.29'" 
ps="'2*int((nf+2)/2) * (W/nf + 0.29)'"
nrd="'0.29 / W'" nrs="'0.29 / W'"
sa=0 sb=0 sd=0
model=nfet_01v8
spiceprefix=X
W=0.5}
C {madvlsi/nmos3.sym} 2500 -800 3 0 {name=M62
L=8

body=GND
nf=1
mult=1
ad="'int((nf+1)/2) * W/nf * 0.29'" 
pd="'2*int((nf+1)/2) * (W/nf + 0.29)'"
as="'int((nf+2)/2) * W/nf * 0.29'" 
ps="'2*int((nf+2)/2) * (W/nf + 0.29)'"
nrd="'0.29 / W'" nrs="'0.29 / W'"
sa=0 sb=0 sd=0
model=nfet_01v8
spiceprefix=X
W=0.5}
C {madvlsi/nmos3.sym} 2410 -800 1 1 {name=M63
L=8

body=GND
nf=1
mult=1
ad="'int((nf+1)/2) * W/nf * 0.29'" 
pd="'2*int((nf+1)/2) * (W/nf + 0.29)'"
as="'int((nf+2)/2) * W/nf * 0.29'" 
ps="'2*int((nf+2)/2) * (W/nf + 0.29)'"
nrd="'0.29 / W'" nrs="'0.29 / W'"
sa=0 sb=0 sd=0
model=nfet_01v8
spiceprefix=X
W=0.5}
C {madvlsi/nmos3.sym} 2500 -630 3 0 {name=M64
L=8

body=GND
nf=1
mult=1
ad="'int((nf+1)/2) * W/nf * 0.29'" 
pd="'2*int((nf+1)/2) * (W/nf + 0.29)'"
as="'int((nf+2)/2) * W/nf * 0.29'" 
ps="'2*int((nf+2)/2) * (W/nf + 0.29)'"
nrd="'0.29 / W'" nrs="'0.29 / W'"
sa=0 sb=0 sd=0
model=nfet_01v8
spiceprefix=X
W=0.5}
C {madvlsi/nmos3.sym} 2410 -630 1 1 {name=M65
L=8

body=GND
nf=1
mult=1
ad="'int((nf+1)/2) * W/nf * 0.29'" 
pd="'2*int((nf+1)/2) * (W/nf + 0.29)'"
as="'int((nf+2)/2) * W/nf * 0.29'" 
ps="'2*int((nf+2)/2) * (W/nf + 0.29)'"
nrd="'0.29 / W'" nrs="'0.29 / W'"
sa=0 sb=0 sd=0
model=nfet_01v8
spiceprefix=X
W=0.5}
C {madvlsi/nmos3.sym} 2660 -800 1 1 {name=M66
L=8

body=GND
nf=1
mult=1
ad="'int((nf+1)/2) * W/nf * 0.29'" 
pd="'2*int((nf+1)/2) * (W/nf + 0.29)'"
as="'int((nf+2)/2) * W/nf * 0.29'" 
ps="'2*int((nf+2)/2) * (W/nf + 0.29)'"
nrd="'0.29 / W'" nrs="'0.29 / W'"
sa=0 sb=0 sd=0
model=nfet_01v8
spiceprefix=X
W=0.5}
C {madvlsi/nmos3.sym} 2750 -800 3 0 {name=M67
L=8

body=GND
nf=1
mult=1
ad="'int((nf+1)/2) * W/nf * 0.29'" 
pd="'2*int((nf+1)/2) * (W/nf + 0.29)'"
as="'int((nf+2)/2) * W/nf * 0.29'" 
ps="'2*int((nf+2)/2) * (W/nf + 0.29)'"
nrd="'0.29 / W'" nrs="'0.29 / W'"
sa=0 sb=0 sd=0
model=nfet_01v8
spiceprefix=X
W=0.5}
C {madvlsi/nmos3.sym} 2750 -630 3 0 {name=M68
L=8

body=GND
nf=1
mult=1
ad="'int((nf+1)/2) * W/nf * 0.29'" 
pd="'2*int((nf+1)/2) * (W/nf + 0.29)'"
as="'int((nf+2)/2) * W/nf * 0.29'" 
ps="'2*int((nf+2)/2) * (W/nf + 0.29)'"
nrd="'0.29 / W'" nrs="'0.29 / W'"
sa=0 sb=0 sd=0
model=nfet_01v8
spiceprefix=X
W=0.5}
C {madvlsi/nmos3.sym} 2660 -630 1 1 {name=M69
L=8

body=GND
nf=1
mult=1
ad="'int((nf+1)/2) * W/nf * 0.29'" 
pd="'2*int((nf+1)/2) * (W/nf + 0.29)'"
as="'int((nf+2)/2) * W/nf * 0.29'" 
ps="'2*int((nf+2)/2) * (W/nf + 0.29)'"
nrd="'0.29 / W'" nrs="'0.29 / W'"
sa=0 sb=0 sd=0
model=nfet_01v8
spiceprefix=X
W=0.5}
C {madvlsi/nmos3.sym} 2940 -800 3 0 {name=M70
L=8

body=GND
nf=1
mult=1
ad="'int((nf+1)/2) * W/nf * 0.29'" 
pd="'2*int((nf+1)/2) * (W/nf + 0.29)'"
as="'int((nf+2)/2) * W/nf * 0.29'" 
ps="'2*int((nf+2)/2) * (W/nf + 0.29)'"
nrd="'0.29 / W'" nrs="'0.29 / W'"
sa=0 sb=0 sd=0
model=nfet_01v8
spiceprefix=X
W=0.5}
C {madvlsi/nmos3.sym} 2850 -800 1 1 {name=M71
L=8

body=GND
nf=1
mult=1
ad="'int((nf+1)/2) * W/nf * 0.29'" 
pd="'2*int((nf+1)/2) * (W/nf + 0.29)'"
as="'int((nf+2)/2) * W/nf * 0.29'" 
ps="'2*int((nf+2)/2) * (W/nf + 0.29)'"
nrd="'0.29 / W'" nrs="'0.29 / W'"
sa=0 sb=0 sd=0
model=nfet_01v8
spiceprefix=X
W=0.5}
C {madvlsi/nmos3.sym} 2940 -630 3 0 {name=M72
L=8

body=GND
nf=1
mult=1
ad="'int((nf+1)/2) * W/nf * 0.29'" 
pd="'2*int((nf+1)/2) * (W/nf + 0.29)'"
as="'int((nf+2)/2) * W/nf * 0.29'" 
ps="'2*int((nf+2)/2) * (W/nf + 0.29)'"
nrd="'0.29 / W'" nrs="'0.29 / W'"
sa=0 sb=0 sd=0
model=nfet_01v8
spiceprefix=X
W=0.5}
C {madvlsi/nmos3.sym} 2850 -630 1 1 {name=M73
L=8

body=GND
nf=1
mult=1
ad="'int((nf+1)/2) * W/nf * 0.29'" 
pd="'2*int((nf+1)/2) * (W/nf + 0.29)'"
as="'int((nf+2)/2) * W/nf * 0.29'" 
ps="'2*int((nf+2)/2) * (W/nf + 0.29)'"
nrd="'0.29 / W'" nrs="'0.29 / W'"
sa=0 sb=0 sd=0
model=nfet_01v8
spiceprefix=X
W=0.5}
C {madvlsi/nmos3.sym} 3100 -800 1 1 {name=M74
L=8

body=GND
nf=1
mult=1
ad="'int((nf+1)/2) * W/nf * 0.29'" 
pd="'2*int((nf+1)/2) * (W/nf + 0.29)'"
as="'int((nf+2)/2) * W/nf * 0.29'" 
ps="'2*int((nf+2)/2) * (W/nf + 0.29)'"
nrd="'0.29 / W'" nrs="'0.29 / W'"
sa=0 sb=0 sd=0
model=nfet_01v8
spiceprefix=X
W=0.5}
C {madvlsi/nmos3.sym} 3190 -800 3 0 {name=M75
L=8

body=GND
nf=1
mult=1
ad="'int((nf+1)/2) * W/nf * 0.29'" 
pd="'2*int((nf+1)/2) * (W/nf + 0.29)'"
as="'int((nf+2)/2) * W/nf * 0.29'" 
ps="'2*int((nf+2)/2) * (W/nf + 0.29)'"
nrd="'0.29 / W'" nrs="'0.29 / W'"
sa=0 sb=0 sd=0
model=nfet_01v8
spiceprefix=X
W=0.5}
C {madvlsi/nmos3.sym} 3190 -630 3 0 {name=M76
L=8

body=GND
nf=1
mult=1
ad="'int((nf+1)/2) * W/nf * 0.29'" 
pd="'2*int((nf+1)/2) * (W/nf + 0.29)'"
as="'int((nf+2)/2) * W/nf * 0.29'" 
ps="'2*int((nf+2)/2) * (W/nf + 0.29)'"
nrd="'0.29 / W'" nrs="'0.29 / W'"
sa=0 sb=0 sd=0
model=nfet_01v8
spiceprefix=X
W=0.5}
C {madvlsi/nmos3.sym} 3100 -630 1 1 {name=M77
L=8

body=GND
nf=1
mult=1
ad="'int((nf+1)/2) * W/nf * 0.29'" 
pd="'2*int((nf+1)/2) * (W/nf + 0.29)'"
as="'int((nf+2)/2) * W/nf * 0.29'" 
ps="'2*int((nf+2)/2) * (W/nf + 0.29)'"
nrd="'0.29 / W'" nrs="'0.29 / W'"
sa=0 sb=0 sd=0
model=nfet_01v8
spiceprefix=X
W=0.5}
C {devices/opin.sym} 3520 -480 0 0 {name=p16 lab=Idump}
C {devices/opin.sym} 3520 -450 0 0 {name=p17 lab=Iout}
C {madvlsi/nmos3.sym} 3290 -800 1 1 {name=M78
L=8

body=GND
nf=1
mult=1
ad="'int((nf+1)/2) * W/nf * 0.29'" 
pd="'2*int((nf+1)/2) * (W/nf + 0.29)'"
as="'int((nf+2)/2) * W/nf * 0.29'" 
ps="'2*int((nf+2)/2) * (W/nf + 0.29)'"
nrd="'0.29 / W'" nrs="'0.29 / W'"
sa=0 sb=0 sd=0
model=nfet_01v8
spiceprefix=X
W=0.5}
C {madvlsi/nmos3.sym} 3380 -800 3 0 {name=M79
L=8

body=GND
nf=1
mult=1
ad="'int((nf+1)/2) * W/nf * 0.29'" 
pd="'2*int((nf+1)/2) * (W/nf + 0.29)'"
as="'int((nf+2)/2) * W/nf * 0.29'" 
ps="'2*int((nf+2)/2) * (W/nf + 0.29)'"
nrd="'0.29 / W'" nrs="'0.29 / W'"
sa=0 sb=0 sd=0
model=nfet_01v8
spiceprefix=X
W=0.5}
C {devices/ipin.sym} 460 -250 1 1 {name=p1 lab=V6}
C {devices/ipin.sym} 900 -250 3 0 {name=p13 lab=V5}
C {devices/ipin.sym} 1340 -250 3 0 {name=p18 lab=V4}
C {devices/ipin.sym} 1780 -250 3 0 {name=p19 lab=V3}
C {devices/ipin.sym} 2220 -250 3 0 {name=p20 lab=V2}
C {devices/ipin.sym} 2660 -250 3 0 {name=p21 lab=V1}
C {devices/ipin.sym} 3100 -250 3 0 {name=p22 lab=V0}
C {madvlsi/nmos3.sym} 130 -630 3 0 {name=M1
L=8

body=GND
nf=1
mult=1
ad="'int((nf+1)/2) * W/nf * 0.29'" 
pd="'2*int((nf+1)/2) * (W/nf + 0.29)'"
as="'int((nf+2)/2) * W/nf * 0.29'" 
ps="'2*int((nf+2)/2) * (W/nf + 0.29)'"
nrd="'0.29 / W'" nrs="'0.29 / W'"
sa=0 sb=0 sd=0
model=nfet_01v8
spiceprefix=X
W=0.5}
C {madvlsi/nmos3.sym} 130 -800 3 0 {name=M2
L=8

body=GND
nf=1
mult=1
ad="'int((nf+1)/2) * W/nf * 0.29'" 
pd="'2*int((nf+1)/2) * (W/nf + 0.29)'"
as="'int((nf+2)/2) * W/nf * 0.29'" 
ps="'2*int((nf+2)/2) * (W/nf + 0.29)'"
nrd="'0.29 / W'" nrs="'0.29 / W'"
sa=0 sb=0 sd=0
model=nfet_01v8
spiceprefix=X
W=0.5}
C {madvlsi/nmos3.sym} 3470 -800 1 1 {name=M3
L=8

body=GND
nf=1
mult=1
ad="'int((nf+1)/2) * W/nf * 0.29'" 
pd="'2*int((nf+1)/2) * (W/nf + 0.29)'"
as="'int((nf+2)/2) * W/nf * 0.29'" 
ps="'2*int((nf+2)/2) * (W/nf + 0.29)'"
nrd="'0.29 / W'" nrs="'0.29 / W'"
sa=0 sb=0 sd=0
model=nfet_01v8
spiceprefix=X
W=0.5}
C {devices/iopin.sym} 100 -700 2 0 {name=p2 lab=VN}
C {madvlsi/nmos3.sym} 3280 -630 1 1 {name=M4
L=8

body=GND
nf=1
mult=1
ad="'int((nf+1)/2) * W/nf * 0.29'" 
pd="'2*int((nf+1)/2) * (W/nf + 0.29)'"
as="'int((nf+2)/2) * W/nf * 0.29'" 
ps="'2*int((nf+2)/2) * (W/nf + 0.29)'"
nrd="'0.29 / W'" nrs="'0.29 / W'"
sa=0 sb=0 sd=0
model=nfet_01v8
spiceprefix=X
W=0.5}
C {devices/ipin.sym} 550 -400 1 1 {name=p3 lab=V6i}
C {devices/ipin.sym} 990 -400 3 0 {name=p4 lab=V5i}
C {devices/ipin.sym} 1430 -400 3 0 {name=p5 lab=V4i}
C {devices/ipin.sym} 1870 -400 3 0 {name=p6 lab=V3i}
C {devices/ipin.sym} 2310 -400 3 0 {name=p7 lab=V2i}
C {devices/ipin.sym} 2750 -400 3 0 {name=p8 lab=V1i}
C {devices/ipin.sym} 3190 -400 3 0 {name=p9 lab=V0i}
